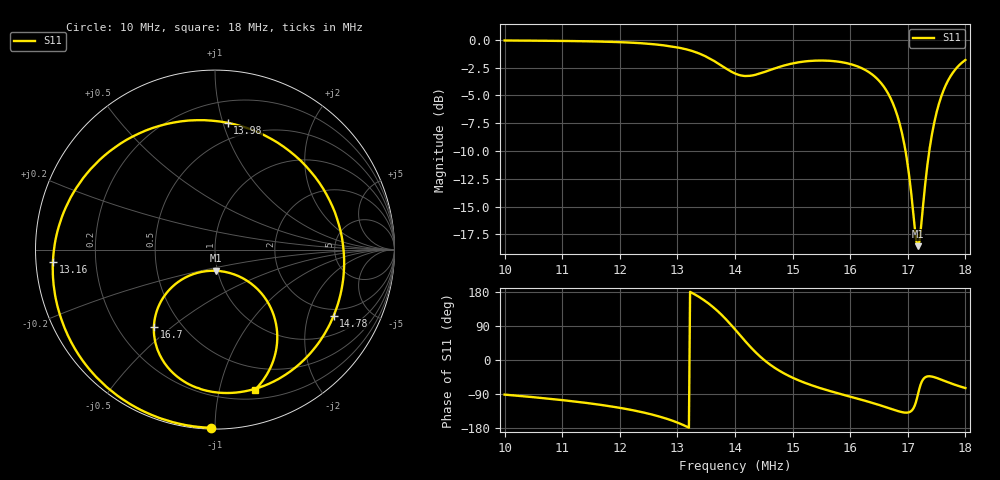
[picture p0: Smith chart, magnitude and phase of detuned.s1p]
! NanoVNA Web complex sweep
! Processing: original sample grid, no browser smoothing
# Hz S RI R 50
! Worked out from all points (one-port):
!   401 points, 10 MHz to 18 MHz, reference 50 ohm
!   lowest |S11| = -18.6 dB at 17.18 MHz (marker M1), VSWR 1.27, Z = 49 - j11.7 ohm
!   |S11| at or under -10 dB: 16.96 MHz to 17.37 MHz (412.5 kHz wide, 2.4 % of centre)
!   S11 on the Smith chart (normalised r, x): 10 MHz: 0.01, -0.98; 13.16 MHz: 0.05, -0.04; 13.98 MHz: 0.36, +1.04; 14.78 MHz: 1.70, -2.94; 16.7 MHz: 0.35, -0.43; 18 MHz: 0.28, -1.29
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1e7  -0.0235 -0.9932
1.1e7  -0.2693 -0.9514
1.2e7  -0.5772 -0.7877
1.256e7  -0.7741 -0.563
1.3e7  -0.8935 -0.2374
1.316e7  -0.9032 -0.0681
1.338e7  -0.8424 0.2095
1.356e7  -0.6912 0.4504
1.38e7  -0.3097 0.6894
1.398e7  0.0703 0.7066
1.4e7  0.1126 0.697
1.418e7  0.4492 0.5206
1.436e7  0.6547 0.2396
1.454e7  0.7194 -0.0528
1.478e7  0.6609 -0.3695
1.5e7  0.5376 -0.57
1.546e7  0.2331 -0.7728
1.6e7  -0.0915 -0.7717
1.636e7  -0.2649 -0.654
1.67e7  -0.3404 -0.4285
1.686e7  -0.302 -0.2903
1.7e7  -0.2043 -0.1796
1.714e7  -0.0477 -0.1199
1.718e7  0.00362 -0.1181
1.738e7  0.2385 -0.2218
1.752e7  0.3283 -0.3691
1.772e7  0.3357 -0.5814
1.8e7  0.2228 -0.7812
